VERSION 5.8 ;
BUSBITCHARS "[]" ;
DIVIDERCHAR "/" ;
UNITS
    DATABASE MICRONS 1000 ;
END UNITS

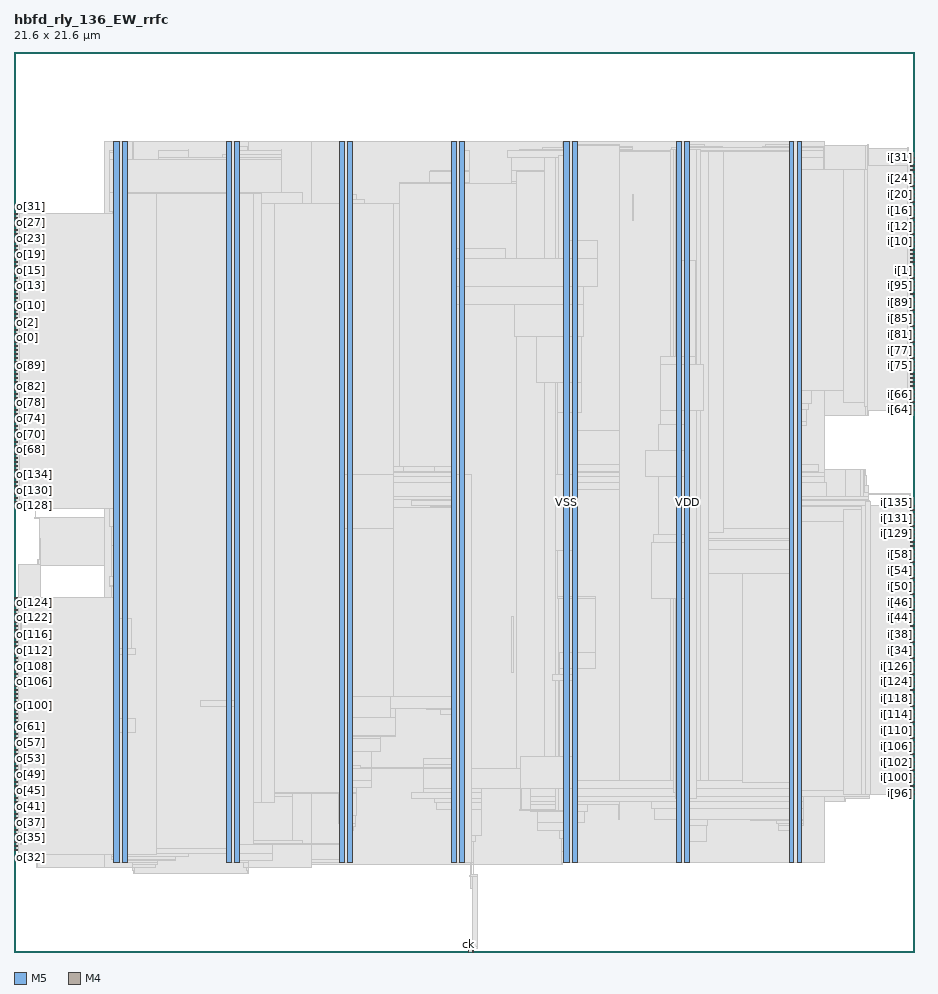
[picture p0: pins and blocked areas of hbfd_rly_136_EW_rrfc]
MACRO hbfd_rly_136_EW_rrfc
  FOREIGN hbfd_rly_136_EW_rrfc 0 0 ;
  CLASS BLOCK ;
  SIZE 21.6 BY 21.6 ;
  PIN ck
    DIRECTION INPUT ;
    USE SIGNAL ;
    PORT
      LAYER M5 ;
        RECT  10.896 0 10.92 0.084 ;
    END
  END ck
  PIN i[0]
    DIRECTION INPUT ;
    USE SIGNAL ;
    PORT
      LAYER M4 ;
        RECT  21.516 16.08 21.6 16.104 ;
    END
  END i[0]
  PIN i[100]
    DIRECTION INPUT ;
    USE SIGNAL ;
    PORT
      LAYER M4 ;
        RECT  21.516 4.176 21.6 4.2 ;
    END
  END i[100]
  PIN i[101]
    DIRECTION INPUT ;
    USE SIGNAL ;
    PORT
      LAYER M4 ;
        RECT  21.516 4.272 21.6 4.296 ;
    END
  END i[101]
  PIN i[102]
    DIRECTION INPUT ;
    USE SIGNAL ;
    PORT
      LAYER M4 ;
        RECT  21.516 4.368 21.6 4.392 ;
    END
  END i[102]
  PIN i[103]
    DIRECTION INPUT ;
    USE SIGNAL ;
    PORT
      LAYER M4 ;
        RECT  21.516 4.464 21.6 4.488 ;
    END
  END i[103]
  PIN i[104]
    DIRECTION INPUT ;
    USE SIGNAL ;
    PORT
      LAYER M4 ;
        RECT  21.516 4.56 21.6 4.584 ;
    END
  END i[104]
  PIN i[105]
    DIRECTION INPUT ;
    USE SIGNAL ;
    PORT
      LAYER M4 ;
        RECT  21.516 4.656 21.6 4.68 ;
    END
  END i[105]
  PIN i[106]
    DIRECTION INPUT ;
    USE SIGNAL ;
    PORT
      LAYER M4 ;
        RECT  21.516 4.752 21.6 4.776 ;
    END
  END i[106]
  PIN i[107]
    DIRECTION INPUT ;
    USE SIGNAL ;
    PORT
      LAYER M4 ;
        RECT  21.516 4.848 21.6 4.872 ;
    END
  END i[107]
  PIN i[108]
    DIRECTION INPUT ;
    USE SIGNAL ;
    PORT
      LAYER M4 ;
        RECT  21.516 4.944 21.6 4.968 ;
    END
  END i[108]
  PIN i[109]
    DIRECTION INPUT ;
    USE SIGNAL ;
    PORT
      LAYER M4 ;
        RECT  21.516 5.04 21.6 5.064 ;
    END
  END i[109]
  PIN i[10]
    DIRECTION INPUT ;
    USE SIGNAL ;
    PORT
      LAYER M4 ;
        RECT  21.516 17.04 21.6 17.064 ;
    END
  END i[10]
  PIN i[110]
    DIRECTION INPUT ;
    USE SIGNAL ;
    PORT
      LAYER M4 ;
        RECT  21.516 5.136 21.6 5.16 ;
    END
  END i[110]
  PIN i[111]
    DIRECTION INPUT ;
    USE SIGNAL ;
    PORT
      LAYER M4 ;
        RECT  21.516 5.232 21.6 5.256 ;
    END
  END i[111]
  PIN i[112]
    DIRECTION INPUT ;
    USE SIGNAL ;
    PORT
      LAYER M4 ;
        RECT  21.516 5.328 21.6 5.352 ;
    END
  END i[112]
  PIN i[113]
    DIRECTION INPUT ;
    USE SIGNAL ;
    PORT
      LAYER M4 ;
        RECT  21.516 5.424 21.6 5.448 ;
    END
  END i[113]
  PIN i[114]
    DIRECTION INPUT ;
    USE SIGNAL ;
    PORT
      LAYER M4 ;
        RECT  21.516 5.52 21.6 5.544 ;
    END
  END i[114]
  PIN i[115]
    DIRECTION INPUT ;
    USE SIGNAL ;
    PORT
      LAYER M4 ;
        RECT  21.516 5.616 21.6 5.64 ;
    END
  END i[115]
  PIN i[116]
    DIRECTION INPUT ;
    USE SIGNAL ;
    PORT
      LAYER M4 ;
        RECT  21.516 5.712 21.6 5.736 ;
    END
  END i[116]
  PIN i[117]
    DIRECTION INPUT ;
    USE SIGNAL ;
    PORT
      LAYER M4 ;
        RECT  21.516 5.808 21.6 5.832 ;
    END
  END i[117]
  PIN i[118]
    DIRECTION INPUT ;
    USE SIGNAL ;
    PORT
      LAYER M4 ;
        RECT  21.516 5.904 21.6 5.928 ;
    END
  END i[118]
  PIN i[119]
    DIRECTION INPUT ;
    USE SIGNAL ;
    PORT
      LAYER M4 ;
        RECT  21.516 6 21.6 6.024 ;
    END
  END i[119]
  PIN i[11]
    DIRECTION INPUT ;
    USE SIGNAL ;
    PORT
      LAYER M4 ;
        RECT  21.516 17.136 21.6 17.16 ;
    END
  END i[11]
  PIN i[120]
    DIRECTION INPUT ;
    USE SIGNAL ;
    PORT
      LAYER M4 ;
        RECT  21.516 6.096 21.6 6.12 ;
    END
  END i[120]
  PIN i[121]
    DIRECTION INPUT ;
    USE SIGNAL ;
    PORT
      LAYER M4 ;
        RECT  21.516 6.192 21.6 6.216 ;
    END
  END i[121]
  PIN i[122]
    DIRECTION INPUT ;
    USE SIGNAL ;
    PORT
      LAYER M4 ;
        RECT  21.516 6.288 21.6 6.312 ;
    END
  END i[122]
  PIN i[123]
    DIRECTION INPUT ;
    USE SIGNAL ;
    PORT
      LAYER M4 ;
        RECT  21.516 6.384 21.6 6.408 ;
    END
  END i[123]
  PIN i[124]
    DIRECTION INPUT ;
    USE SIGNAL ;
    PORT
      LAYER M4 ;
        RECT  21.516 6.48 21.6 6.504 ;
    END
  END i[124]
  PIN i[125]
    DIRECTION INPUT ;
    USE SIGNAL ;
    PORT
      LAYER M4 ;
        RECT  21.516 6.576 21.6 6.6 ;
    END
  END i[125]
  PIN i[126]
    DIRECTION INPUT ;
    USE SIGNAL ;
    PORT
      LAYER M4 ;
        RECT  21.516 6.672 21.6 6.696 ;
    END
  END i[126]
  PIN i[127]
    DIRECTION INPUT ;
    USE SIGNAL ;
    PORT
      LAYER M4 ;
        RECT  21.516 6.768 21.6 6.792 ;
    END
  END i[127]
  PIN i[128]
    DIRECTION INPUT ;
    USE SIGNAL ;
    PORT
      LAYER M4 ;
        RECT  21.516 9.936 21.6 9.96 ;
    END
  END i[128]
  PIN i[129]
    DIRECTION INPUT ;
    USE SIGNAL ;
    PORT
      LAYER M4 ;
        RECT  21.516 10.032 21.6 10.056 ;
    END
  END i[129]
  PIN i[12]
    DIRECTION INPUT ;
    USE SIGNAL ;
    PORT
      LAYER M4 ;
        RECT  21.516 17.232 21.6 17.256 ;
    END
  END i[12]
  PIN i[130]
    DIRECTION INPUT ;
    USE SIGNAL ;
    PORT
      LAYER M4 ;
        RECT  21.516 10.128 21.6 10.152 ;
    END
  END i[130]
  PIN i[131]
    DIRECTION INPUT ;
    USE SIGNAL ;
    PORT
      LAYER M4 ;
        RECT  21.516 10.224 21.6 10.248 ;
    END
  END i[131]
  PIN i[132]
    DIRECTION INPUT ;
    USE SIGNAL ;
    PORT
      LAYER M4 ;
        RECT  21.516 10.32 21.6 10.344 ;
    END
  END i[132]
  PIN i[133]
    DIRECTION INPUT ;
    USE SIGNAL ;
    PORT
      LAYER M4 ;
        RECT  21.516 10.416 21.6 10.44 ;
    END
  END i[133]
  PIN i[134]
    DIRECTION INPUT ;
    USE SIGNAL ;
    PORT
      LAYER M4 ;
        RECT  21.516 10.512 21.6 10.536 ;
    END
  END i[134]
  PIN i[135]
    DIRECTION INPUT ;
    USE SIGNAL ;
    PORT
      LAYER M4 ;
        RECT  21.516 10.608 21.6 10.632 ;
    END
  END i[135]
  PIN i[13]
    DIRECTION INPUT ;
    USE SIGNAL ;
    PORT
      LAYER M4 ;
        RECT  21.516 17.328 21.6 17.352 ;
    END
  END i[13]
  PIN i[14]
    DIRECTION INPUT ;
    USE SIGNAL ;
    PORT
      LAYER M4 ;
        RECT  21.516 17.424 21.6 17.448 ;
    END
  END i[14]
  PIN i[15]
    DIRECTION INPUT ;
    USE SIGNAL ;
    PORT
      LAYER M4 ;
        RECT  21.516 17.52 21.6 17.544 ;
    END
  END i[15]
  PIN i[16]
    DIRECTION INPUT ;
    USE SIGNAL ;
    PORT
      LAYER M4 ;
        RECT  21.516 17.616 21.6 17.64 ;
    END
  END i[16]
  PIN i[17]
    DIRECTION INPUT ;
    USE SIGNAL ;
    PORT
      LAYER M4 ;
        RECT  21.516 17.712 21.6 17.736 ;
    END
  END i[17]
  PIN i[18]
    DIRECTION INPUT ;
    USE SIGNAL ;
    PORT
      LAYER M4 ;
        RECT  21.516 17.808 21.6 17.832 ;
    END
  END i[18]
  PIN i[19]
    DIRECTION INPUT ;
    USE SIGNAL ;
    PORT
      LAYER M4 ;
        RECT  21.516 17.904 21.6 17.928 ;
    END
  END i[19]
  PIN i[1]
    DIRECTION INPUT ;
    USE SIGNAL ;
    PORT
      LAYER M4 ;
        RECT  21.516 16.176 21.6 16.2 ;
    END
  END i[1]
  PIN i[20]
    DIRECTION INPUT ;
    USE SIGNAL ;
    PORT
      LAYER M4 ;
        RECT  21.516 18 21.6 18.024 ;
    END
  END i[20]
  PIN i[21]
    DIRECTION INPUT ;
    USE SIGNAL ;
    PORT
      LAYER M4 ;
        RECT  21.516 18.096 21.6 18.12 ;
    END
  END i[21]
  PIN i[22]
    DIRECTION INPUT ;
    USE SIGNAL ;
    PORT
      LAYER M4 ;
        RECT  21.516 18.192 21.6 18.216 ;
    END
  END i[22]
  PIN i[23]
    DIRECTION INPUT ;
    USE SIGNAL ;
    PORT
      LAYER M4 ;
        RECT  21.516 18.288 21.6 18.312 ;
    END
  END i[23]
  PIN i[24]
    DIRECTION INPUT ;
    USE SIGNAL ;
    PORT
      LAYER M4 ;
        RECT  21.516 18.384 21.6 18.408 ;
    END
  END i[24]
  PIN i[25]
    DIRECTION INPUT ;
    USE SIGNAL ;
    PORT
      LAYER M4 ;
        RECT  21.516 18.48 21.6 18.504 ;
    END
  END i[25]
  PIN i[26]
    DIRECTION INPUT ;
    USE SIGNAL ;
    PORT
      LAYER M4 ;
        RECT  21.516 18.576 21.6 18.6 ;
    END
  END i[26]
  PIN i[27]
    DIRECTION INPUT ;
    USE SIGNAL ;
    PORT
      LAYER M4 ;
        RECT  21.516 18.672 21.6 18.696 ;
    END
  END i[27]
  PIN i[28]
    DIRECTION INPUT ;
    USE SIGNAL ;
    PORT
      LAYER M4 ;
        RECT  21.516 18.768 21.6 18.792 ;
    END
  END i[28]
  PIN i[29]
    DIRECTION INPUT ;
    USE SIGNAL ;
    PORT
      LAYER M4 ;
        RECT  21.516 18.864 21.6 18.888 ;
    END
  END i[29]
  PIN i[2]
    DIRECTION INPUT ;
    USE SIGNAL ;
    PORT
      LAYER M4 ;
        RECT  21.516 16.272 21.6 16.296 ;
    END
  END i[2]
  PIN i[30]
    DIRECTION INPUT ;
    USE SIGNAL ;
    PORT
      LAYER M4 ;
        RECT  21.516 18.96 21.6 18.984 ;
    END
  END i[30]
  PIN i[31]
    DIRECTION INPUT ;
    USE SIGNAL ;
    PORT
      LAYER M4 ;
        RECT  21.516 19.056 21.6 19.08 ;
    END
  END i[31]
  PIN i[32]
    DIRECTION INPUT ;
    USE SIGNAL ;
    PORT
      LAYER M4 ;
        RECT  21.516 6.864 21.6 6.888 ;
    END
  END i[32]
  PIN i[33]
    DIRECTION INPUT ;
    USE SIGNAL ;
    PORT
      LAYER M4 ;
        RECT  21.516 6.96 21.6 6.984 ;
    END
  END i[33]
  PIN i[34]
    DIRECTION INPUT ;
    USE SIGNAL ;
    PORT
      LAYER M4 ;
        RECT  21.516 7.056 21.6 7.08 ;
    END
  END i[34]
  PIN i[35]
    DIRECTION INPUT ;
    USE SIGNAL ;
    PORT
      LAYER M4 ;
        RECT  21.516 7.152 21.6 7.176 ;
    END
  END i[35]
  PIN i[36]
    DIRECTION INPUT ;
    USE SIGNAL ;
    PORT
      LAYER M4 ;
        RECT  21.516 7.248 21.6 7.272 ;
    END
  END i[36]
  PIN i[37]
    DIRECTION INPUT ;
    USE SIGNAL ;
    PORT
      LAYER M4 ;
        RECT  21.516 7.344 21.6 7.368 ;
    END
  END i[37]
  PIN i[38]
    DIRECTION INPUT ;
    USE SIGNAL ;
    PORT
      LAYER M4 ;
        RECT  21.516 7.44 21.6 7.464 ;
    END
  END i[38]
  PIN i[39]
    DIRECTION INPUT ;
    USE SIGNAL ;
    PORT
      LAYER M4 ;
        RECT  21.516 7.536 21.6 7.56 ;
    END
  END i[39]
  PIN i[3]
    DIRECTION INPUT ;
    USE SIGNAL ;
    PORT
      LAYER M4 ;
        RECT  21.516 16.368 21.6 16.392 ;
    END
  END i[3]
  PIN i[40]
    DIRECTION INPUT ;
    USE SIGNAL ;
    PORT
      LAYER M4 ;
        RECT  21.516 7.632 21.6 7.656 ;
    END
  END i[40]
  PIN i[41]
    DIRECTION INPUT ;
    USE SIGNAL ;
    PORT
      LAYER M4 ;
        RECT  21.516 7.728 21.6 7.752 ;
    END
  END i[41]
  PIN i[42]
    DIRECTION INPUT ;
    USE SIGNAL ;
    PORT
      LAYER M4 ;
        RECT  21.516 7.824 21.6 7.848 ;
    END
  END i[42]
  PIN i[43]
    DIRECTION INPUT ;
    USE SIGNAL ;
    PORT
      LAYER M4 ;
        RECT  21.516 7.92 21.6 7.944 ;
    END
  END i[43]
  PIN i[44]
    DIRECTION INPUT ;
    USE SIGNAL ;
    PORT
      LAYER M4 ;
        RECT  21.516 8.016 21.6 8.04 ;
    END
  END i[44]
  PIN i[45]
    DIRECTION INPUT ;
    USE SIGNAL ;
    PORT
      LAYER M4 ;
        RECT  21.516 8.112 21.6 8.136 ;
    END
  END i[45]
  PIN i[46]
    DIRECTION INPUT ;
    USE SIGNAL ;
    PORT
      LAYER M4 ;
        RECT  21.516 8.208 21.6 8.232 ;
    END
  END i[46]
  PIN i[47]
    DIRECTION INPUT ;
    USE SIGNAL ;
    PORT
      LAYER M4 ;
        RECT  21.516 8.304 21.6 8.328 ;
    END
  END i[47]
  PIN i[48]
    DIRECTION INPUT ;
    USE SIGNAL ;
    PORT
      LAYER M4 ;
        RECT  21.516 8.4 21.6 8.424 ;
    END
  END i[48]
  PIN i[49]
    DIRECTION INPUT ;
    USE SIGNAL ;
    PORT
      LAYER M4 ;
        RECT  21.516 8.496 21.6 8.52 ;
    END
  END i[49]
  PIN i[4]
    DIRECTION INPUT ;
    USE SIGNAL ;
    PORT
      LAYER M4 ;
        RECT  21.516 16.464 21.6 16.488 ;
    END
  END i[4]
  PIN i[50]
    DIRECTION INPUT ;
    USE SIGNAL ;
    PORT
      LAYER M4 ;
        RECT  21.516 8.592 21.6 8.616 ;
    END
  END i[50]
  PIN i[51]
    DIRECTION INPUT ;
    USE SIGNAL ;
    PORT
      LAYER M4 ;
        RECT  21.516 8.688 21.6 8.712 ;
    END
  END i[51]
  PIN i[52]
    DIRECTION INPUT ;
    USE SIGNAL ;
    PORT
      LAYER M4 ;
        RECT  21.516 8.784 21.6 8.808 ;
    END
  END i[52]
  PIN i[53]
    DIRECTION INPUT ;
    USE SIGNAL ;
    PORT
      LAYER M4 ;
        RECT  21.516 8.88 21.6 8.904 ;
    END
  END i[53]
  PIN i[54]
    DIRECTION INPUT ;
    USE SIGNAL ;
    PORT
      LAYER M4 ;
        RECT  21.516 8.976 21.6 9 ;
    END
  END i[54]
  PIN i[55]
    DIRECTION INPUT ;
    USE SIGNAL ;
    PORT
      LAYER M4 ;
        RECT  21.516 9.072 21.6 9.096 ;
    END
  END i[55]
  PIN i[56]
    DIRECTION INPUT ;
    USE SIGNAL ;
    PORT
      LAYER M4 ;
        RECT  21.516 9.168 21.6 9.192 ;
    END
  END i[56]
  PIN i[57]
    DIRECTION INPUT ;
    USE SIGNAL ;
    PORT
      LAYER M4 ;
        RECT  21.516 9.264 21.6 9.288 ;
    END
  END i[57]
  PIN i[58]
    DIRECTION INPUT ;
    USE SIGNAL ;
    PORT
      LAYER M4 ;
        RECT  21.516 9.36 21.6 9.384 ;
    END
  END i[58]
  PIN i[59]
    DIRECTION INPUT ;
    USE SIGNAL ;
    PORT
      LAYER M4 ;
        RECT  21.516 9.456 21.6 9.48 ;
    END
  END i[59]
  PIN i[5]
    DIRECTION INPUT ;
    USE SIGNAL ;
    PORT
      LAYER M4 ;
        RECT  21.516 16.56 21.6 16.584 ;
    END
  END i[5]
  PIN i[60]
    DIRECTION INPUT ;
    USE SIGNAL ;
    PORT
      LAYER M4 ;
        RECT  21.516 9.552 21.6 9.576 ;
    END
  END i[60]
  PIN i[61]
    DIRECTION INPUT ;
    USE SIGNAL ;
    PORT
      LAYER M4 ;
        RECT  21.516 9.648 21.6 9.672 ;
    END
  END i[61]
  PIN i[62]
    DIRECTION INPUT ;
    USE SIGNAL ;
    PORT
      LAYER M4 ;
        RECT  21.516 9.744 21.6 9.768 ;
    END
  END i[62]
  PIN i[63]
    DIRECTION INPUT ;
    USE SIGNAL ;
    PORT
      LAYER M4 ;
        RECT  21.516 9.84 21.6 9.864 ;
    END
  END i[63]
  PIN i[64]
    DIRECTION INPUT ;
    USE SIGNAL ;
    PORT
      LAYER M4 ;
        RECT  21.516 13.008 21.6 13.032 ;
    END
  END i[64]
  PIN i[65]
    DIRECTION INPUT ;
    USE SIGNAL ;
    PORT
      LAYER M4 ;
        RECT  21.516 13.104 21.6 13.128 ;
    END
  END i[65]
  PIN i[66]
    DIRECTION INPUT ;
    USE SIGNAL ;
    PORT
      LAYER M4 ;
        RECT  21.516 13.2 21.6 13.224 ;
    END
  END i[66]
  PIN i[67]
    DIRECTION INPUT ;
    USE SIGNAL ;
    PORT
      LAYER M4 ;
        RECT  21.516 13.296 21.6 13.32 ;
    END
  END i[67]
  PIN i[68]
    DIRECTION INPUT ;
    USE SIGNAL ;
    PORT
      LAYER M4 ;
        RECT  21.516 13.392 21.6 13.416 ;
    END
  END i[68]
  PIN i[69]
    DIRECTION INPUT ;
    USE SIGNAL ;
    PORT
      LAYER M4 ;
        RECT  21.516 13.488 21.6 13.512 ;
    END
  END i[69]
  PIN i[6]
    DIRECTION INPUT ;
    USE SIGNAL ;
    PORT
      LAYER M4 ;
        RECT  21.516 16.656 21.6 16.68 ;
    END
  END i[6]
  PIN i[70]
    DIRECTION INPUT ;
    USE SIGNAL ;
    PORT
      LAYER M4 ;
        RECT  21.516 13.584 21.6 13.608 ;
    END
  END i[70]
  PIN i[71]
    DIRECTION INPUT ;
    USE SIGNAL ;
    PORT
      LAYER M4 ;
        RECT  21.516 13.68 21.6 13.704 ;
    END
  END i[71]
  PIN i[72]
    DIRECTION INPUT ;
    USE SIGNAL ;
    PORT
      LAYER M4 ;
        RECT  21.516 13.776 21.6 13.8 ;
    END
  END i[72]
  PIN i[73]
    DIRECTION INPUT ;
    USE SIGNAL ;
    PORT
      LAYER M4 ;
        RECT  21.516 13.872 21.6 13.896 ;
    END
  END i[73]
  PIN i[74]
    DIRECTION INPUT ;
    USE SIGNAL ;
    PORT
      LAYER M4 ;
        RECT  21.516 13.968 21.6 13.992 ;
    END
  END i[74]
  PIN i[75]
    DIRECTION INPUT ;
    USE SIGNAL ;
    PORT
      LAYER M4 ;
        RECT  21.516 14.064 21.6 14.088 ;
    END
  END i[75]
  PIN i[76]
    DIRECTION INPUT ;
    USE SIGNAL ;
    PORT
      LAYER M4 ;
        RECT  21.516 14.16 21.6 14.184 ;
    END
  END i[76]
  PIN i[77]
    DIRECTION INPUT ;
    USE SIGNAL ;
    PORT
      LAYER M4 ;
        RECT  21.516 14.256 21.6 14.28 ;
    END
  END i[77]
  PIN i[78]
    DIRECTION INPUT ;
    USE SIGNAL ;
    PORT
      LAYER M4 ;
        RECT  21.516 14.352 21.6 14.376 ;
    END
  END i[78]
  PIN i[79]
    DIRECTION INPUT ;
    USE SIGNAL ;
    PORT
      LAYER M4 ;
        RECT  21.516 14.448 21.6 14.472 ;
    END
  END i[79]
  PIN i[7]
    DIRECTION INPUT ;
    USE SIGNAL ;
    PORT
      LAYER M4 ;
        RECT  21.516 16.752 21.6 16.776 ;
    END
  END i[7]
  PIN i[80]
    DIRECTION INPUT ;
    USE SIGNAL ;
    PORT
      LAYER M4 ;
        RECT  21.516 14.544 21.6 14.568 ;
    END
  END i[80]
  PIN i[81]
    DIRECTION INPUT ;
    USE SIGNAL ;
    PORT
      LAYER M4 ;
        RECT  21.516 14.64 21.6 14.664 ;
    END
  END i[81]
  PIN i[82]
    DIRECTION INPUT ;
    USE SIGNAL ;
    PORT
      LAYER M4 ;
        RECT  21.516 14.736 21.6 14.76 ;
    END
  END i[82]
  PIN i[83]
    DIRECTION INPUT ;
    USE SIGNAL ;
    PORT
      LAYER M4 ;
        RECT  21.516 14.832 21.6 14.856 ;
    END
  END i[83]
  PIN i[84]
    DIRECTION INPUT ;
    USE SIGNAL ;
    PORT
      LAYER M4 ;
        RECT  21.516 14.928 21.6 14.952 ;
    END
  END i[84]
  PIN i[85]
    DIRECTION INPUT ;
    USE SIGNAL ;
    PORT
      LAYER M4 ;
        RECT  21.516 15.024 21.6 15.048 ;
    END
  END i[85]
  PIN i[86]
    DIRECTION INPUT ;
    USE SIGNAL ;
    PORT
      LAYER M4 ;
        RECT  21.516 15.12 21.6 15.144 ;
    END
  END i[86]
  PIN i[87]
    DIRECTION INPUT ;
    USE SIGNAL ;
    PORT
      LAYER M4 ;
        RECT  21.516 15.216 21.6 15.24 ;
    END
  END i[87]
  PIN i[88]
    DIRECTION INPUT ;
    USE SIGNAL ;
    PORT
      LAYER M4 ;
        RECT  21.516 15.312 21.6 15.336 ;
    END
  END i[88]
  PIN i[89]
    DIRECTION INPUT ;
    USE SIGNAL ;
    PORT
      LAYER M4 ;
        RECT  21.516 15.408 21.6 15.432 ;
    END
  END i[89]
  PIN i[8]
    DIRECTION INPUT ;
    USE SIGNAL ;
    PORT
      LAYER M4 ;
        RECT  21.516 16.848 21.6 16.872 ;
    END
  END i[8]
  PIN i[90]
    DIRECTION INPUT ;
    USE SIGNAL ;
    PORT
      LAYER M4 ;
        RECT  21.516 15.504 21.6 15.528 ;
    END
  END i[90]
  PIN i[91]
    DIRECTION INPUT ;
    USE SIGNAL ;
    PORT
      LAYER M4 ;
        RECT  21.516 15.6 21.6 15.624 ;
    END
  END i[91]
  PIN i[92]
    DIRECTION INPUT ;
    USE SIGNAL ;
    PORT
      LAYER M4 ;
        RECT  21.516 15.696 21.6 15.72 ;
    END
  END i[92]
  PIN i[93]
    DIRECTION INPUT ;
    USE SIGNAL ;
    PORT
      LAYER M4 ;
        RECT  21.516 15.792 21.6 15.816 ;
    END
  END i[93]
  PIN i[94]
    DIRECTION INPUT ;
    USE SIGNAL ;
    PORT
      LAYER M4 ;
        RECT  21.516 15.888 21.6 15.912 ;
    END
  END i[94]
  PIN i[95]
    DIRECTION INPUT ;
    USE SIGNAL ;
    PORT
      LAYER M4 ;
        RECT  21.516 15.984 21.6 16.008 ;
    END
  END i[95]
  PIN i[96]
    DIRECTION INPUT ;
    USE SIGNAL ;
    PORT
      LAYER M4 ;
        RECT  21.516 3.792 21.6 3.816 ;
    END
  END i[96]
  PIN i[97]
    DIRECTION INPUT ;
    USE SIGNAL ;
    PORT
      LAYER M4 ;
        RECT  21.516 3.888 21.6 3.912 ;
    END
  END i[97]
  PIN i[98]
    DIRECTION INPUT ;
    USE SIGNAL ;
    PORT
      LAYER M4 ;
        RECT  21.516 3.984 21.6 4.008 ;
    END
  END i[98]
  PIN i[99]
    DIRECTION INPUT ;
    USE SIGNAL ;
    PORT
      LAYER M4 ;
        RECT  21.516 4.08 21.6 4.104 ;
    END
  END i[99]
  PIN i[9]
    DIRECTION INPUT ;
    USE SIGNAL ;
    PORT
      LAYER M4 ;
        RECT  21.516 16.944 21.6 16.968 ;
    END
  END i[9]
  PIN o[0]
    DIRECTION OUTPUT ;
    USE SIGNAL ;
    PORT
      LAYER M4 ;
        RECT  0 14.736 0.084 14.76 ;
    END
  END o[0]
  PIN o[100]
    DIRECTION OUTPUT ;
    USE SIGNAL ;
    PORT
      LAYER M4 ;
        RECT  0 5.904 0.084 5.928 ;
    END
  END o[100]
  PIN o[101]
    DIRECTION OUTPUT ;
    USE SIGNAL ;
    PORT
      LAYER M4 ;
        RECT  0 6 0.084 6.024 ;
    END
  END o[101]
  PIN o[102]
    DIRECTION OUTPUT ;
    USE SIGNAL ;
    PORT
      LAYER M4 ;
        RECT  0 6.096 0.084 6.12 ;
    END
  END o[102]
  PIN o[103]
    DIRECTION OUTPUT ;
    USE SIGNAL ;
    PORT
      LAYER M4 ;
        RECT  0 6.192 0.084 6.216 ;
    END
  END o[103]
  PIN o[104]
    DIRECTION OUTPUT ;
    USE SIGNAL ;
    PORT
      LAYER M4 ;
        RECT  0 6.288 0.084 6.312 ;
    END
  END o[104]
  PIN o[105]
    DIRECTION OUTPUT ;
    USE SIGNAL ;
    PORT
      LAYER M4 ;
        RECT  0 6.384 0.084 6.408 ;
    END
  END o[105]
  PIN o[106]
    DIRECTION OUTPUT ;
    USE SIGNAL ;
    PORT
      LAYER M4 ;
        RECT  0 6.48 0.084 6.504 ;
    END
  END o[106]
  PIN o[107]
    DIRECTION OUTPUT ;
    USE SIGNAL ;
    PORT
      LAYER M4 ;
        RECT  0 6.576 0.084 6.6 ;
    END
  END o[107]
  PIN o[108]
    DIRECTION OUTPUT ;
    USE SIGNAL ;
    PORT
      LAYER M4 ;
        RECT  0 6.672 0.084 6.696 ;
    END
  END o[108]
  PIN o[109]
    DIRECTION OUTPUT ;
    USE SIGNAL ;
    PORT
      LAYER M4 ;
        RECT  0 6.768 0.084 6.792 ;
    END
  END o[109]
  PIN o[10]
    DIRECTION OUTPUT ;
    USE SIGNAL ;
    PORT
      LAYER M4 ;
        RECT  0 15.696 0.084 15.72 ;
    END
  END o[10]
  PIN o[110]
    DIRECTION OUTPUT ;
    USE SIGNAL ;
    PORT
      LAYER M4 ;
        RECT  0 6.864 0.084 6.888 ;
    END
  END o[110]
  PIN o[111]
    DIRECTION OUTPUT ;
    USE SIGNAL ;
    PORT
      LAYER M4 ;
        RECT  0 6.96 0.084 6.984 ;
    END
  END o[111]
  PIN o[112]
    DIRECTION OUTPUT ;
    USE SIGNAL ;
    PORT
      LAYER M4 ;
        RECT  0 7.056 0.084 7.08 ;
    END
  END o[112]
  PIN o[113]
    DIRECTION OUTPUT ;
    USE SIGNAL ;
    PORT
      LAYER M4 ;
        RECT  0 7.152 0.084 7.176 ;
    END
  END o[113]
  PIN o[114]
    DIRECTION OUTPUT ;
    USE SIGNAL ;
    PORT
      LAYER M4 ;
        RECT  0 7.248 0.084 7.272 ;
    END
  END o[114]
  PIN o[115]
    DIRECTION OUTPUT ;
    USE SIGNAL ;
    PORT
      LAYER M4 ;
        RECT  0 7.344 0.084 7.368 ;
    END
  END o[115]
  PIN o[116]
    DIRECTION OUTPUT ;
    USE SIGNAL ;
    PORT
      LAYER M4 ;
        RECT  0 7.44 0.084 7.464 ;
    END
  END o[116]
  PIN o[117]
    DIRECTION OUTPUT ;
    USE SIGNAL ;
    PORT
      LAYER M4 ;
        RECT  0 7.536 0.084 7.56 ;
    END
  END o[117]
  PIN o[118]
    DIRECTION OUTPUT ;
    USE SIGNAL ;
    PORT
      LAYER M4 ;
        RECT  0 7.632 0.084 7.656 ;
    END
  END o[118]
  PIN o[119]
    DIRECTION OUTPUT ;
    USE SIGNAL ;
    PORT
      LAYER M4 ;
        RECT  0 7.728 0.084 7.752 ;
    END
  END o[119]
  PIN o[11]
    DIRECTION OUTPUT ;
    USE SIGNAL ;
    PORT
      LAYER M4 ;
        RECT  0 15.792 0.084 15.816 ;
    END
  END o[11]
  PIN o[120]
    DIRECTION OUTPUT ;
    USE SIGNAL ;
    PORT
      LAYER M4 ;
        RECT  0 7.824 0.084 7.848 ;
    END
  END o[120]
  PIN o[121]
    DIRECTION OUTPUT ;
    USE SIGNAL ;
    PORT
      LAYER M4 ;
        RECT  0 7.92 0.084 7.944 ;
    END
  END o[121]
  PIN o[122]
    DIRECTION OUTPUT ;
    USE SIGNAL ;
    PORT
      LAYER M4 ;
        RECT  0 8.016 0.084 8.04 ;
    END
  END o[122]
  PIN o[123]
    DIRECTION OUTPUT ;
    USE SIGNAL ;
    PORT
      LAYER M4 ;
        RECT  0 8.112 0.084 8.136 ;
    END
  END o[123]
  PIN o[124]
    DIRECTION OUTPUT ;
    USE SIGNAL ;
    PORT
      LAYER M4 ;
        RECT  0 8.208 0.084 8.232 ;
    END
  END o[124]
  PIN o[125]
    DIRECTION OUTPUT ;
    USE SIGNAL ;
    PORT
      LAYER M4 ;
        RECT  0 8.304 0.084 8.328 ;
    END
  END o[125]
  PIN o[126]
    DIRECTION OUTPUT ;
    USE SIGNAL ;
    PORT
      LAYER M4 ;
        RECT  0 8.4 0.084 8.424 ;
    END
  END o[126]
  PIN o[127]
    DIRECTION OUTPUT ;
    USE SIGNAL ;
    PORT
      LAYER M4 ;
        RECT  0 8.496 0.084 8.52 ;
    END
  END o[127]
  PIN o[128]
    DIRECTION OUTPUT ;
    USE SIGNAL ;
    PORT
      LAYER M4 ;
        RECT  0 10.704 0.084 10.728 ;
    END
  END o[128]
  PIN o[129]
    DIRECTION OUTPUT ;
    USE SIGNAL ;
    PORT
      LAYER M4 ;
        RECT  0 10.8 0.084 10.824 ;
    END
  END o[129]
  PIN o[12]
    DIRECTION OUTPUT ;
    USE SIGNAL ;
    PORT
      LAYER M4 ;
        RECT  0 15.888 0.084 15.912 ;
    END
  END o[12]
  PIN o[130]
    DIRECTION OUTPUT ;
    USE SIGNAL ;
    PORT
      LAYER M4 ;
        RECT  0 10.896 0.084 10.92 ;
    END
  END o[130]
  PIN o[131]
    DIRECTION OUTPUT ;
    USE SIGNAL ;
    PORT
      LAYER M4 ;
        RECT  0 10.992 0.084 11.016 ;
    END
  END o[131]
  PIN o[132]
    DIRECTION OUTPUT ;
    USE SIGNAL ;
    PORT
      LAYER M4 ;
        RECT  0 11.088 0.084 11.112 ;
    END
  END o[132]
  PIN o[133]
    DIRECTION OUTPUT ;
    USE SIGNAL ;
    PORT
      LAYER M4 ;
        RECT  0 11.184 0.084 11.208 ;
    END
  END o[133]
  PIN o[134]
    DIRECTION OUTPUT ;
    USE SIGNAL ;
    PORT
      LAYER M4 ;
        RECT  0 11.28 0.084 11.304 ;
    END
  END o[134]
  PIN o[135]
    DIRECTION OUTPUT ;
    USE SIGNAL ;
    PORT
      LAYER M4 ;
        RECT  0 11.376 0.084 11.4 ;
    END
  END o[135]
  PIN o[13]
    DIRECTION OUTPUT ;
    USE SIGNAL ;
    PORT
      LAYER M4 ;
        RECT  0 15.984 0.084 16.008 ;
    END
  END o[13]
  PIN o[14]
    DIRECTION OUTPUT ;
    USE SIGNAL ;
    PORT
      LAYER M4 ;
        RECT  0 16.08 0.084 16.104 ;
    END
  END o[14]
  PIN o[15]
    DIRECTION OUTPUT ;
    USE SIGNAL ;
    PORT
      LAYER M4 ;
        RECT  0 16.176 0.084 16.2 ;
    END
  END o[15]
  PIN o[16]
    DIRECTION OUTPUT ;
    USE SIGNAL ;
    PORT
      LAYER M4 ;
        RECT  0 16.272 0.084 16.296 ;
    END
  END o[16]
  PIN o[17]
    DIRECTION OUTPUT ;
    USE SIGNAL ;
    PORT
      LAYER M4 ;
        RECT  0 16.368 0.084 16.392 ;
    END
  END o[17]
  PIN o[18]
    DIRECTION OUTPUT ;
    USE SIGNAL ;
    PORT
      LAYER M4 ;
        RECT  0 16.464 0.084 16.488 ;
    END
  END o[18]
  PIN o[19]
    DIRECTION OUTPUT ;
    USE SIGNAL ;
    PORT
      LAYER M4 ;
        RECT  0 16.56 0.084 16.584 ;
    END
  END o[19]
  PIN o[1]
    DIRECTION OUTPUT ;
    USE SIGNAL ;
    PORT
      LAYER M4 ;
        RECT  0 14.832 0.084 14.856 ;
    END
  END o[1]
  PIN o[20]
    DIRECTION OUTPUT ;
    USE SIGNAL ;
    PORT
      LAYER M4 ;
        RECT  0 16.656 0.084 16.68 ;
    END
  END o[20]
  PIN o[21]
    DIRECTION OUTPUT ;
    USE SIGNAL ;
    PORT
      LAYER M4 ;
        RECT  0 16.752 0.084 16.776 ;
    END
  END o[21]
  PIN o[22]
    DIRECTION OUTPUT ;
    USE SIGNAL ;
    PORT
      LAYER M4 ;
        RECT  0 16.848 0.084 16.872 ;
    END
  END o[22]
  PIN o[23]
    DIRECTION OUTPUT ;
    USE SIGNAL ;
    PORT
      LAYER M4 ;
        RECT  0 16.944 0.084 16.968 ;
    END
  END o[23]
  PIN o[24]
    DIRECTION OUTPUT ;
    USE SIGNAL ;
    PORT
      LAYER M4 ;
        RECT  0 17.04 0.084 17.064 ;
    END
  END o[24]
  PIN o[25]
    DIRECTION OUTPUT ;
    USE SIGNAL ;
    PORT
      LAYER M4 ;
        RECT  0 17.136 0.084 17.16 ;
    END
  END o[25]
  PIN o[26]
    DIRECTION OUTPUT ;
    USE SIGNAL ;
    PORT
      LAYER M4 ;
        RECT  0 17.232 0.084 17.256 ;
    END
  END o[26]
  PIN o[27]
    DIRECTION OUTPUT ;
    USE SIGNAL ;
    PORT
      LAYER M4 ;
        RECT  0 17.328 0.084 17.352 ;
    END
  END o[27]
  PIN o[28]
    DIRECTION OUTPUT ;
    USE SIGNAL ;
    PORT
      LAYER M4 ;
        RECT  0 17.424 0.084 17.448 ;
    END
  END o[28]
  PIN o[29]
    DIRECTION OUTPUT ;
    USE SIGNAL ;
    PORT
      LAYER M4 ;
        RECT  0 17.52 0.084 17.544 ;
    END
  END o[29]
  PIN o[2]
    DIRECTION OUTPUT ;
    USE SIGNAL ;
    PORT
      LAYER M4 ;
        RECT  0 14.928 0.084 14.952 ;
    END
  END o[2]
  PIN o[30]
    DIRECTION OUTPUT ;
    USE SIGNAL ;
    PORT
      LAYER M4 ;
        RECT  0 17.616 0.084 17.64 ;
    END
  END o[30]
  PIN o[31]
    DIRECTION OUTPUT ;
    USE SIGNAL ;
    PORT
      LAYER M4 ;
        RECT  0 17.712 0.084 17.736 ;
    END
  END o[31]
  PIN o[32]
    DIRECTION OUTPUT ;
    USE SIGNAL ;
    PORT
      LAYER M4 ;
        RECT  0 2.448 0.084 2.472 ;
    END
  END o[32]
  PIN o[33]
    DIRECTION OUTPUT ;
    USE SIGNAL ;
    PORT
      LAYER M4 ;
        RECT  0 2.544 0.084 2.568 ;
    END
  END o[33]
  PIN o[34]
    DIRECTION OUTPUT ;
    USE SIGNAL ;
    PORT
      LAYER M4 ;
        RECT  0 2.64 0.084 2.664 ;
    END
  END o[34]
  PIN o[35]
    DIRECTION OUTPUT ;
    USE SIGNAL ;
    PORT
      LAYER M4 ;
        RECT  0 2.736 0.084 2.76 ;
    END
  END o[35]
  PIN o[36]
    DIRECTION OUTPUT ;
    USE SIGNAL ;
    PORT
      LAYER M4 ;
        RECT  0 2.832 0.084 2.856 ;
    END
  END o[36]
  PIN o[37]
    DIRECTION OUTPUT ;
    USE SIGNAL ;
    PORT
      LAYER M4 ;
        RECT  0 2.928 0.084 2.952 ;
    END
  END o[37]
  PIN o[38]
    DIRECTION OUTPUT ;
    USE SIGNAL ;
    PORT
      LAYER M4 ;
        RECT  0 3.024 0.084 3.048 ;
    END
  END o[38]
  PIN o[39]
    DIRECTION OUTPUT ;
    USE SIGNAL ;
    PORT
      LAYER M4 ;
        RECT  0 3.12 0.084 3.144 ;
    END
  END o[39]
  PIN o[3]
    DIRECTION OUTPUT ;
    USE SIGNAL ;
    PORT
      LAYER M4 ;
        RECT  0 15.024 0.084 15.048 ;
    END
  END o[3]
  PIN o[40]
    DIRECTION OUTPUT ;
    USE SIGNAL ;
    PORT
      LAYER M4 ;
        RECT  0 3.216 0.084 3.24 ;
    END
  END o[40]
  PIN o[41]
    DIRECTION OUTPUT ;
    USE SIGNAL ;
    PORT
      LAYER M4 ;
        RECT  0 3.312 0.084 3.336 ;
    END
  END o[41]
  PIN o[42]
    DIRECTION OUTPUT ;
    USE SIGNAL ;
    PORT
      LAYER M4 ;
        RECT  0 3.408 0.084 3.432 ;
    END
  END o[42]
  PIN o[43]
    DIRECTION OUTPUT ;
    USE SIGNAL ;
    PORT
      LAYER M4 ;
        RECT  0 3.504 0.084 3.528 ;
    END
  END o[43]
  PIN o[44]
    DIRECTION OUTPUT ;
    USE SIGNAL ;
    PORT
      LAYER M4 ;
        RECT  0 3.6 0.084 3.624 ;
    END
  END o[44]
  PIN o[45]
    DIRECTION OUTPUT ;
    USE SIGNAL ;
    PORT
      LAYER M4 ;
        RECT  0 3.696 0.084 3.72 ;
    END
  END o[45]
  PIN o[46]
    DIRECTION OUTPUT ;
    USE SIGNAL ;
    PORT
      LAYER M4 ;
        RECT  0 3.792 0.084 3.816 ;
    END
  END o[46]
  PIN o[47]
    DIRECTION OUTPUT ;
    USE SIGNAL ;
    PORT
      LAYER M4 ;
        RECT  0 3.888 0.084 3.912 ;
    END
  END o[47]
  PIN o[48]
    DIRECTION OUTPUT ;
    USE SIGNAL ;
    PORT
      LAYER M4 ;
        RECT  0 3.984 0.084 4.008 ;
    END
  END o[48]
  PIN o[49]
    DIRECTION OUTPUT ;
    USE SIGNAL ;
    PORT
      LAYER M4 ;
        RECT  0 4.08 0.084 4.104 ;
    END
  END o[49]
  PIN o[4]
    DIRECTION OUTPUT ;
    USE SIGNAL ;
    PORT
      LAYER M4 ;
        RECT  0 15.12 0.084 15.144 ;
    END
  END o[4]
  PIN o[50]
    DIRECTION OUTPUT ;
    USE SIGNAL ;
    PORT
      LAYER M4 ;
        RECT  0 4.176 0.084 4.2 ;
    END
  END o[50]
  PIN o[51]
    DIRECTION OUTPUT ;
    USE SIGNAL ;
    PORT
      LAYER M4 ;
        RECT  0 4.272 0.084 4.296 ;
    END
  END o[51]
  PIN o[52]
    DIRECTION OUTPUT ;
    USE SIGNAL ;
    PORT
      LAYER M4 ;
        RECT  0 4.368 0.084 4.392 ;
    END
  END o[52]
  PIN o[53]
    DIRECTION OUTPUT ;
    USE SIGNAL ;
    PORT
      LAYER M4 ;
        RECT  0 4.464 0.084 4.488 ;
    END
  END o[53]
  PIN o[54]
    DIRECTION OUTPUT ;
    USE SIGNAL ;
    PORT
      LAYER M4 ;
        RECT  0 4.56 0.084 4.584 ;
    END
  END o[54]
  PIN o[55]
    DIRECTION OUTPUT ;
    USE SIGNAL ;
    PORT
      LAYER M4 ;
        RECT  0 4.656 0.084 4.68 ;
    END
  END o[55]
  PIN o[56]
    DIRECTION OUTPUT ;
    USE SIGNAL ;
    PORT
      LAYER M4 ;
        RECT  0 4.752 0.084 4.776 ;
    END
  END o[56]
  PIN o[57]
    DIRECTION OUTPUT ;
    USE SIGNAL ;
    PORT
      LAYER M4 ;
        RECT  0 4.848 0.084 4.872 ;
    END
  END o[57]
  PIN o[58]
    DIRECTION OUTPUT ;
    USE SIGNAL ;
    PORT
      LAYER M4 ;
        RECT  0 4.944 0.084 4.968 ;
    END
  END o[58]
  PIN o[59]
    DIRECTION OUTPUT ;
    USE SIGNAL ;
    PORT
      LAYER M4 ;
        RECT  0 5.04 0.084 5.064 ;
    END
  END o[59]
  PIN o[5]
    DIRECTION OUTPUT ;
    USE SIGNAL ;
    PORT
      LAYER M4 ;
        RECT  0 15.216 0.084 15.24 ;
    END
  END o[5]
  PIN o[60]
    DIRECTION OUTPUT ;
    USE SIGNAL ;
    PORT
      LAYER M4 ;
        RECT  0 5.136 0.084 5.16 ;
    END
  END o[60]
  PIN o[61]
    DIRECTION OUTPUT ;
    USE SIGNAL ;
    PORT
      LAYER M4 ;
        RECT  0 5.232 0.084 5.256 ;
    END
  END o[61]
  PIN o[62]
    DIRECTION OUTPUT ;
    USE SIGNAL ;
    PORT
      LAYER M4 ;
        RECT  0 5.328 0.084 5.352 ;
    END
  END o[62]
  PIN o[63]
    DIRECTION OUTPUT ;
    USE SIGNAL ;
    PORT
      LAYER M4 ;
        RECT  0 5.424 0.084 5.448 ;
    END
  END o[63]
  PIN o[64]
    DIRECTION OUTPUT ;
    USE SIGNAL ;
    PORT
      LAYER M4 ;
        RECT  0 11.664 0.084 11.688 ;
    END
  END o[64]
  PIN o[65]
    DIRECTION OUTPUT ;
    USE SIGNAL ;
    PORT
      LAYER M4 ;
        RECT  0 11.76 0.084 11.784 ;
    END
  END o[65]
  PIN o[66]
    DIRECTION OUTPUT ;
    USE SIGNAL ;
    PORT
      LAYER M4 ;
        RECT  0 11.856 0.084 11.88 ;
    END
  END o[66]
  PIN o[67]
    DIRECTION OUTPUT ;
    USE SIGNAL ;
    PORT
      LAYER M4 ;
        RECT  0 11.952 0.084 11.976 ;
    END
  END o[67]
  PIN o[68]
    DIRECTION OUTPUT ;
    USE SIGNAL ;
    PORT
      LAYER M4 ;
        RECT  0 12.048 0.084 12.072 ;
    END
  END o[68]
  PIN o[69]
    DIRECTION OUTPUT ;
    USE SIGNAL ;
    PORT
      LAYER M4 ;
        RECT  0 12.144 0.084 12.168 ;
    END
  END o[69]
  PIN o[6]
    DIRECTION OUTPUT ;
    USE SIGNAL ;
    PORT
      LAYER M4 ;
        RECT  0 15.312 0.084 15.336 ;
    END
  END o[6]
  PIN o[70]
    DIRECTION OUTPUT ;
    USE SIGNAL ;
    PORT
      LAYER M4 ;
        RECT  0 12.24 0.084 12.264 ;
    END
  END o[70]
  PIN o[71]
    DIRECTION OUTPUT ;
    USE SIGNAL ;
    PORT
      LAYER M4 ;
        RECT  0 12.336 0.084 12.36 ;
    END
  END o[71]
  PIN o[72]
    DIRECTION OUTPUT ;
    USE SIGNAL ;
    PORT
      LAYER M4 ;
        RECT  0 12.432 0.084 12.456 ;
    END
  END o[72]
  PIN o[73]
    DIRECTION OUTPUT ;
    USE SIGNAL ;
    PORT
      LAYER M4 ;
        RECT  0 12.528 0.084 12.552 ;
    END
  END o[73]
  PIN o[74]
    DIRECTION OUTPUT ;
    USE SIGNAL ;
    PORT
      LAYER M4 ;
        RECT  0 12.624 0.084 12.648 ;
    END
  END o[74]
  PIN o[75]
    DIRECTION OUTPUT ;
    USE SIGNAL ;
    PORT
      LAYER M4 ;
        RECT  0 12.72 0.084 12.744 ;
    END
  END o[75]
  PIN o[76]
    DIRECTION OUTPUT ;
    USE SIGNAL ;
    PORT
      LAYER M4 ;
        RECT  0 12.816 0.084 12.84 ;
    END
  END o[76]
  PIN o[77]
    DIRECTION OUTPUT ;
    USE SIGNAL ;
    PORT
      LAYER M4 ;
        RECT  0 12.912 0.084 12.936 ;
    END
  END o[77]
  PIN o[78]
    DIRECTION OUTPUT ;
    USE SIGNAL ;
    PORT
      LAYER M4 ;
        RECT  0 13.008 0.084 13.032 ;
    END
  END o[78]
  PIN o[79]
    DIRECTION OUTPUT ;
    USE SIGNAL ;
    PORT
      LAYER M4 ;
        RECT  0 13.104 0.084 13.128 ;
    END
  END o[79]
  PIN o[7]
    DIRECTION OUTPUT ;
    USE SIGNAL ;
    PORT
      LAYER M4 ;
        RECT  0 15.408 0.084 15.432 ;
    END
  END o[7]
  PIN o[80]
    DIRECTION OUTPUT ;
    USE SIGNAL ;
    PORT
      LAYER M4 ;
        RECT  0 13.2 0.084 13.224 ;
    END
  END o[80]
  PIN o[81]
    DIRECTION OUTPUT ;
    USE SIGNAL ;
    PORT
      LAYER M4 ;
        RECT  0 13.296 0.084 13.32 ;
    END
  END o[81]
  PIN o[82]
    DIRECTION OUTPUT ;
    USE SIGNAL ;
    PORT
      LAYER M4 ;
        RECT  0 13.392 0.084 13.416 ;
    END
  END o[82]
  PIN o[83]
    DIRECTION OUTPUT ;
    USE SIGNAL ;
    PORT
      LAYER M4 ;
        RECT  0 13.488 0.084 13.512 ;
    END
  END o[83]
  PIN o[84]
    DIRECTION OUTPUT ;
    USE SIGNAL ;
    PORT
      LAYER M4 ;
        RECT  0 13.584 0.084 13.608 ;
    END
  END o[84]
  PIN o[85]
    DIRECTION OUTPUT ;
    USE SIGNAL ;
    PORT
      LAYER M4 ;
        RECT  0 13.68 0.084 13.704 ;
    END
  END o[85]
  PIN o[86]
    DIRECTION OUTPUT ;
    USE SIGNAL ;
    PORT
      LAYER M4 ;
        RECT  0 13.776 0.084 13.8 ;
    END
  END o[86]
  PIN o[87]
    DIRECTION OUTPUT ;
    USE SIGNAL ;
    PORT
      LAYER M4 ;
        RECT  0 13.872 0.084 13.896 ;
    END
  END o[87]
  PIN o[88]
    DIRECTION OUTPUT ;
    USE SIGNAL ;
    PORT
      LAYER M4 ;
        RECT  0 13.968 0.084 13.992 ;
    END
  END o[88]
  PIN o[89]
    DIRECTION OUTPUT ;
    USE SIGNAL ;
    PORT
      LAYER M4 ;
        RECT  0 14.064 0.084 14.088 ;
    END
  END o[89]
  PIN o[8]
    DIRECTION OUTPUT ;
    USE SIGNAL ;
    PORT
      LAYER M4 ;
        RECT  0 15.504 0.084 15.528 ;
    END
  END o[8]
  PIN o[90]
    DIRECTION OUTPUT ;
    USE SIGNAL ;
    PORT
      LAYER M4 ;
        RECT  0 14.16 0.084 14.184 ;
    END
  END o[90]
  PIN o[91]
    DIRECTION OUTPUT ;
    USE SIGNAL ;
    PORT
      LAYER M4 ;
        RECT  0 14.256 0.084 14.28 ;
    END
  END o[91]
  PIN o[92]
    DIRECTION OUTPUT ;
    USE SIGNAL ;
    PORT
      LAYER M4 ;
        RECT  0 14.352 0.084 14.376 ;
    END
  END o[92]
  PIN o[93]
    DIRECTION OUTPUT ;
    USE SIGNAL ;
    PORT
      LAYER M4 ;
        RECT  0 14.448 0.084 14.472 ;
    END
  END o[93]
  PIN o[94]
    DIRECTION OUTPUT ;
    USE SIGNAL ;
    PORT
      LAYER M4 ;
        RECT  0 14.544 0.084 14.568 ;
    END
  END o[94]
  PIN o[95]
    DIRECTION OUTPUT ;
    USE SIGNAL ;
    PORT
      LAYER M4 ;
        RECT  0 14.64 0.084 14.664 ;
    END
  END o[95]
  PIN o[96]
    DIRECTION OUTPUT ;
    USE SIGNAL ;
    PORT
      LAYER M4 ;
        RECT  0 5.52 0.084 5.544 ;
    END
  END o[96]
  PIN o[97]
    DIRECTION OUTPUT ;
    USE SIGNAL ;
    PORT
      LAYER M4 ;
        RECT  0 5.616 0.084 5.64 ;
    END
  END o[97]
  PIN o[98]
    DIRECTION OUTPUT ;
    USE SIGNAL ;
    PORT
      LAYER M4 ;
        RECT  0 5.712 0.084 5.736 ;
    END
  END o[98]
  PIN o[99]
    DIRECTION OUTPUT ;
    USE SIGNAL ;
    PORT
      LAYER M4 ;
        RECT  0 5.808 0.084 5.832 ;
    END
  END o[99]
  PIN o[9]
    DIRECTION OUTPUT ;
    USE SIGNAL ;
    PORT
      LAYER M4 ;
        RECT  0 15.6 0.084 15.624 ;
    END
  END o[9]
  PIN rfi
    DIRECTION INPUT ;
    USE SIGNAL ;
    PORT
      LAYER M4 ;
        RECT  21.516 10.704 21.6 10.728 ;
    END
  END rfi
  PIN rfo
    DIRECTION OUTPUT ;
    USE SIGNAL ;
    PORT
      LAYER M4 ;
        RECT  0 11.472 0.084 11.496 ;
    END
  END rfo
  PIN rs
    DIRECTION INPUT ;
    USE SIGNAL ;
    PORT
      LAYER M5 ;
        RECT  10.992 0 11.016 0.084 ;
    END
  END rs
  PIN rso
    DIRECTION OUTPUT ;
    USE SIGNAL ;
    PORT
      LAYER M4 ;
        RECT  0 11.568 0.084 11.592 ;
    END
  END rso
  PIN VDD
    DIRECTION INOUT ;
    USE POWER ;
    PORT
      LAYER M5 ;
        RECT  18.792 2.151 18.912 19.449 ;
        RECT  16.092 2.151 16.212 19.449 ;
        RECT  13.392 2.151 13.512 19.449 ;
        RECT  10.692 2.151 10.812 19.449 ;
        RECT  7.992 2.151 8.112 19.449 ;
        RECT  5.292 2.151 5.412 19.449 ;
        RECT  2.592 2.151 2.712 19.449 ;
    END
  END VDD
  PIN VSS
    DIRECTION INOUT ;
    USE GROUND ;
    PORT
      LAYER M5 ;
        RECT  18.6 2.137 18.72 19.463 ;
        RECT  15.9 2.137 16.02 19.463 ;
        RECT  13.2 2.137 13.32 19.463 ;
        RECT  10.5 2.137 10.62 19.463 ;
        RECT  7.8 2.137 7.92 19.463 ;
        RECT  5.1 2.137 5.22 19.463 ;
        RECT  2.4 2.137 2.52 19.463 ;
    END
  END VSS
  OBS
    LAYER RVTN ;
     RECT  2.16 2.16 19.44 2.295 ;
     RECT  2.16 2.565 19.44 2.835 ;
     RECT  2.16 3.105 19.44 3.375 ;
     RECT  2.16 3.645 19.44 3.915 ;
     RECT  2.16 4.185 19.44 4.455 ;
     RECT  2.16 4.725 19.44 4.995 ;
     RECT  2.16 5.265 19.44 5.535 ;
     RECT  2.16 5.805 19.44 6.075 ;
     RECT  2.16 6.345 19.44 6.615 ;
     RECT  2.16 6.885 19.44 7.155 ;
     RECT  2.16 7.425 19.44 7.695 ;
     RECT  2.16 7.965 19.44 8.235 ;
     RECT  2.16 8.505 19.44 8.775 ;
     RECT  2.16 9.045 19.44 9.315 ;
     RECT  2.16 9.585 19.44 9.855 ;
     RECT  2.16 10.125 19.44 10.395 ;
     RECT  2.16 10.665 19.44 10.935 ;
     RECT  2.16 11.205 19.44 11.475 ;
     RECT  2.16 11.745 19.44 12.015 ;
     RECT  2.16 12.285 19.44 12.555 ;
     RECT  2.16 12.825 19.44 13.095 ;
     RECT  2.16 13.365 19.44 13.635 ;
     RECT  2.16 13.905 19.44 14.175 ;
     RECT  2.16 14.445 19.44 14.715 ;
     RECT  2.16 14.985 19.44 15.255 ;
     RECT  2.16 15.525 19.44 15.795 ;
     RECT  2.16 16.065 19.44 16.335 ;
     RECT  2.16 16.605 19.44 16.875 ;
     RECT  2.16 17.145 19.44 17.415 ;
     RECT  2.16 17.685 19.44 17.955 ;
     RECT  2.16 18.225 19.44 18.495 ;
     RECT  2.16 18.765 19.44 19.035 ;
     RECT  2.16 19.305 19.44 19.44 ;
    LAYER RVTP ;
     RECT  2.16 2.295 19.44 2.565 ;
     RECT  2.16 2.835 19.44 3.105 ;
     RECT  2.16 3.375 19.44 3.645 ;
     RECT  2.16 3.915 19.44 4.185 ;
     RECT  2.16 4.455 19.44 4.725 ;
     RECT  2.16 4.995 19.44 5.265 ;
     RECT  2.16 5.535 19.44 5.805 ;
     RECT  2.16 6.075 19.44 6.345 ;
     RECT  2.16 6.615 19.44 6.885 ;
     RECT  2.16 7.155 19.44 7.425 ;
     RECT  2.16 7.695 19.44 7.965 ;
     RECT  2.16 8.235 19.44 8.505 ;
     RECT  2.16 8.775 19.44 9.045 ;
     RECT  2.16 9.315 19.44 9.585 ;
     RECT  2.16 9.855 19.44 10.125 ;
     RECT  2.16 10.395 19.44 10.665 ;
     RECT  2.16 10.935 19.44 11.205 ;
     RECT  2.16 11.475 19.44 11.745 ;
     RECT  2.16 12.015 19.44 12.285 ;
     RECT  2.16 12.555 19.44 12.825 ;
     RECT  2.16 13.095 19.44 13.365 ;
     RECT  2.16 13.635 19.44 13.905 ;
     RECT  2.16 14.175 19.44 14.445 ;
     RECT  2.16 14.715 19.44 14.985 ;
     RECT  2.16 15.255 19.44 15.525 ;
     RECT  2.16 15.795 19.44 16.065 ;
     RECT  2.16 16.335 19.44 16.605 ;
     RECT  2.16 16.875 19.44 17.145 ;
     RECT  2.16 17.415 19.44 17.685 ;
     RECT  2.16 17.955 19.44 18.225 ;
     RECT  2.16 18.495 19.44 18.765 ;
     RECT  2.16 19.035 19.44 19.305 ;
    LAYER M1 ;
     RECT  2.16 2.151 19.44 19.449 ;
    LAYER M2 ;
     RECT  0.103 3.69 0.175 3.708 ;
     RECT  0.175 3.69 0.203 4.284 ;
     RECT  0.103 5.436 0.203 7.38 ;
     RECT  0.103 10.836 0.203 10.854 ;
     RECT  0.103 12.798 0.203 14.049 ;
     RECT  0.103 16.614 0.203 17.37 ;
     RECT  0.203 7.362 0.239 7.38 ;
     RECT  0.203 4.266 0.275 4.284 ;
     RECT  0.463 2.574 0.499 2.592 ;
     RECT  0.499 2.574 0.535 2.754 ;
     RECT  0.103 9.288 0.571 9.306 ;
     RECT  0.571 9.288 0.607 9.414 ;
     RECT  0.499 10.404 0.607 10.422 ;
     RECT  0.535 14.22 1.183 14.904 ;
     RECT  1.183 13.986 1.211 14.904 ;
     RECT  0.535 2.034 2.16 3.204 ;
     RECT  0.203 5.436 2.16 5.454 ;
     RECT  0.607 9.288 2.16 10.422 ;
     RECT  0.535 11.25 2.16 11.268 ;
     RECT  0.535 12.096 2.16 12.114 ;
     RECT  1.211 13.986 2.16 14.004 ;
     RECT  1.211 14.886 2.16 14.904 ;
     RECT  0.139 15.804 2.16 15.822 ;
     RECT  0.203 16.614 2.16 16.632 ;
     RECT  2.16 2.034 2.839 19.449 ;
     RECT  2.839 1.962 2.875 19.449 ;
     RECT  2.875 1.881 5.639 19.449 ;
     RECT  5.639 2.034 7.151 19.449 ;
     RECT  7.151 2.106 13.163 19.449 ;
     RECT  13.163 2.151 19.44 19.449 ;
     RECT  19.44 3.618 19.967 11.574 ;
     RECT  19.967 3.69 20.327 11.574 ;
     RECT  20.327 9.288 20.399 11.574 ;
     RECT  20.327 3.69 20.435 4.986 ;
     RECT  20.399 9.558 20.435 11.574 ;
     RECT  19.44 12.87 20.435 19.368 ;
     RECT  20.435 10.98 20.471 11.43 ;
     RECT  20.327 5.778 20.507 8.334 ;
     RECT  20.471 10.98 20.507 11.196 ;
     RECT  20.435 12.87 20.507 16.326 ;
     RECT  20.435 17.082 20.507 17.1 ;
     RECT  20.435 18.198 20.507 19.368 ;
     RECT  20.435 3.69 20.543 4.518 ;
     RECT  20.507 5.778 20.543 7.524 ;
     RECT  20.507 14.22 20.543 16.326 ;
     RECT  20.543 3.96 20.579 4.518 ;
     RECT  20.543 14.49 20.579 16.326 ;
     RECT  20.543 5.778 21.443 6.606 ;
     RECT  20.543 7.398 21.443 7.416 ;
     RECT  20.435 9.594 21.443 10.188 ;
     RECT  20.579 14.49 21.443 14.544 ;
     RECT  20.507 8.28 21.479 8.334 ;
     RECT  21.443 9.594 21.479 9.882 ;
     RECT  20.507 18.198 21.479 19.296 ;
     RECT  20.579 3.96 21.515 3.978 ;
     RECT  21.443 5.886 21.515 5.904 ;
     RECT  21.479 8.316 21.515 8.334 ;
     RECT  21.479 9.594 21.515 9.612 ;
     RECT  20.507 10.98 21.515 10.998 ;
     RECT  21.443 14.526 21.515 14.544 ;
     RECT  20.579 15.57 21.515 16.326 ;
     RECT  21.479 18.198 21.515 18.216 ;
     RECT  21.479 19.116 21.515 19.134 ;
    LAYER M3 ;
     RECT  2.88 1.876 2.898 1.957 ;
     RECT  5.616 1.876 5.634 1.957 ;
     RECT  2.844 1.957 2.898 2.029 ;
     RECT  5.58 1.957 5.634 2.029 ;
     RECT  2.844 2.029 3.402 2.101 ;
     RECT  2.844 2.101 3.438 2.143 ;
     RECT  5.508 2.029 5.634 2.143 ;
     RECT  7.128 2.029 7.146 2.143 ;
     RECT  11.016 1.531 11.034 2.143 ;
     RECT  13.14 2.101 13.158 2.143 ;
     RECT  2.415 2.143 3.438 2.191 ;
     RECT  5.115 2.143 5.634 2.191 ;
     RECT  7.128 2.143 7.905 2.219 ;
     RECT  2.415 2.191 3.87 2.227 ;
     RECT  2.34 2.227 3.87 2.299 ;
     RECT  0.54 2.029 0.558 2.347 ;
     RECT  2.34 2.299 4.194 2.371 ;
     RECT  5.115 2.191 6.21 2.371 ;
     RECT  7.815 2.219 7.905 2.413 ;
     RECT  13.14 2.143 13.305 2.413 ;
     RECT  15.915 2.143 16.005 2.413 ;
     RECT  18.615 2.143 18.705 2.413 ;
     RECT  2.34 2.371 6.21 2.569 ;
     RECT  10.515 2.143 11.034 2.641 ;
     RECT  15.915 2.413 16.197 2.641 ;
     RECT  0.108 2.347 0.558 2.669 ;
     RECT  2.34 2.569 6.93 2.669 ;
     RECT  13.14 2.413 13.497 2.731 ;
     RECT  10.515 2.641 11.07 2.803 ;
     RECT  7.815 2.413 8.097 2.911 ;
     RECT  13.104 2.731 13.497 2.911 ;
     RECT  18.615 2.413 18.897 2.911 ;
     RECT  7.815 2.911 8.154 3.001 ;
     RECT  15.915 2.641 16.614 3.037 ;
     RECT  18.36 2.911 18.897 3.037 ;
     RECT  7.815 3.001 8.19 3.073 ;
     RECT  18.36 3.037 18.954 3.073 ;
     RECT  12.564 2.911 13.497 3.109 ;
     RECT  18.288 3.073 18.954 3.145 ;
     RECT  15.915 3.037 16.65 3.181 ;
     RECT  17.676 3.145 18.954 3.181 ;
     RECT  7.776 3.073 8.19 3.271 ;
     RECT  12.564 3.109 13.698 3.379 ;
     RECT  10.515 2.803 11.214 3.415 ;
     RECT  15.372 3.181 18.954 3.451 ;
     RECT  12.384 3.379 13.77 3.541 ;
     RECT  14.508 3.181 14.526 3.541 ;
     RECT  10.152 3.415 11.214 3.577 ;
     RECT  12.384 3.541 14.526 3.613 ;
     RECT  15.3 3.451 18.954 3.613 ;
     RECT  0.144 2.669 0.558 3.676 ;
     RECT  10.08 3.577 11.214 3.685 ;
     RECT  19.944 3.613 19.962 3.685 ;
     RECT  2.34 2.669 6.678 3.721 ;
     RECT  12.384 3.613 18.954 3.721 ;
     RECT  19.944 3.685 20.538 3.721 ;
     RECT  2.304 3.721 6.678 3.811 ;
     RECT  7.776 3.271 8.226 3.811 ;
     RECT  0.108 3.676 0.558 3.821 ;
     RECT  2.304 3.811 8.226 3.839 ;
     RECT  9.54 3.685 11.214 3.839 ;
     RECT  9.828 3.839 11.214 3.919 ;
     RECT  12.384 3.721 20.538 3.919 ;
     RECT  2.34 3.839 8.226 3.955 ;
     RECT  21.492 3.955 21.51 4.013 ;
     RECT  2.34 3.955 8.586 4.109 ;
     RECT  9.828 3.919 20.538 4.492 ;
     RECT  9.828 4.492 20.574 4.649 ;
     RECT  2.415 4.109 8.586 4.801 ;
     RECT  0.144 3.821 0.558 4.877 ;
     RECT  2.415 4.801 8.802 5.131 ;
     RECT  2.304 5.131 8.802 5.161 ;
     RECT  2.304 5.161 9.162 5.189 ;
     RECT  0.144 4.877 0.198 5.419 ;
     RECT  19.836 4.649 20.574 5.515 ;
     RECT  2.34 5.189 9.162 5.639 ;
     RECT  10.515 4.649 18.99 5.701 ;
     RECT  10.224 5.701 18.99 5.707 ;
     RECT  19.8 5.515 20.574 5.707 ;
     RECT  21.42 5.419 21.438 5.803 ;
     RECT  10.224 5.707 20.574 5.809 ;
     RECT  9.036 5.639 9.162 5.845 ;
     RECT  9.9 5.809 20.574 5.845 ;
     RECT  21.42 5.803 21.51 5.909 ;
     RECT  9.036 5.845 20.574 6.221 ;
     RECT  2.34 5.639 8.097 6.691 ;
     RECT  2.304 6.691 8.097 7.195 ;
     RECT  9.036 6.221 20.538 7.195 ;
     RECT  0.108 5.419 0.198 7.243 ;
     RECT  2.304 7.195 20.538 7.349 ;
     RECT  0.108 7.243 0.342 7.385 ;
     RECT  21.42 5.909 21.438 7.421 ;
     RECT  7.38 7.349 20.538 7.661 ;
     RECT  7.38 7.661 20.502 7.691 ;
     RECT  0.216 7.385 0.342 7.723 ;
     RECT  7.38 7.691 9.054 7.763 ;
     RECT  2.304 7.349 6.39 7.889 ;
     RECT  0.216 7.723 0.594 8.107 ;
     RECT  7.38 7.763 8.514 8.159 ;
     RECT  7.38 8.159 8.097 8.167 ;
     RECT  9.9 7.691 20.502 8.231 ;
     RECT  2.34 7.889 6.39 8.239 ;
     RECT  7.272 8.167 8.097 8.239 ;
     RECT  21.492 8.203 21.51 8.275 ;
     RECT  21.456 8.275 21.51 8.333 ;
     RECT  0.108 8.107 0.594 8.395 ;
     RECT  2.34 8.239 8.097 8.779 ;
     RECT  2.304 8.779 8.097 8.807 ;
     RECT  9.9 8.231 20.322 8.971 ;
     RECT  2.304 8.807 6.75 9.005 ;
     RECT  21.492 8.333 21.51 9.259 ;
     RECT  0.108 8.395 0.63 9.311 ;
     RECT  21.456 9.259 21.51 9.355 ;
     RECT  0.576 9.311 0.63 9.419 ;
     RECT  21.42 9.355 21.51 9.617 ;
     RECT  9.9 8.971 20.43 9.661 ;
     RECT  2.34 9.005 6.75 9.751 ;
     RECT  7.815 8.807 8.097 9.751 ;
     RECT  9.828 9.661 20.43 9.887 ;
     RECT  0.612 9.419 0.63 9.923 ;
     RECT  10.008 9.887 20.43 9.931 ;
     RECT  21.42 9.617 21.474 10.193 ;
     RECT  2.34 9.751 8.097 10.201 ;
     RECT  0.504 10.399 0.522 10.651 ;
     RECT  10.008 9.931 20.502 10.699 ;
     RECT  10.008 10.699 20.538 10.705 ;
     RECT  0.144 10.651 0.522 10.828 ;
     RECT  9.54 10.705 20.538 10.829 ;
     RECT  9.54 10.829 20.502 10.867 ;
     RECT  8.928 10.867 20.502 10.931 ;
     RECT  0.108 10.828 0.522 10.939 ;
     RECT  21.492 10.507 21.51 11.003 ;
     RECT  20.376 10.931 20.502 11.039 ;
     RECT  0.108 10.939 1.17 11.117 ;
     RECT  20.412 11.039 20.502 11.201 ;
     RECT  0.144 11.117 1.17 11.227 ;
     RECT  8.928 10.931 19.494 11.273 ;
     RECT  0.144 11.227 1.242 11.405 ;
     RECT  2.304 10.201 8.097 11.419 ;
     RECT  8.928 11.273 19.458 11.419 ;
     RECT  20.412 11.201 20.466 11.435 ;
     RECT  2.304 11.419 19.458 11.507 ;
     RECT  2.304 11.507 19.314 11.543 ;
     RECT  20.412 11.435 20.43 11.579 ;
     RECT  10.08 11.543 19.314 11.705 ;
     RECT  9.036 11.543 9.342 11.975 ;
     RECT  0.144 11.405 1.17 11.981 ;
     RECT  2.304 11.543 8.154 12.283 ;
     RECT  9.324 11.975 9.342 12.559 ;
     RECT  10.08 11.705 18.897 12.559 ;
     RECT  9.324 12.559 18.897 12.631 ;
     RECT  2.304 12.283 8.586 12.721 ;
     RECT  9.324 12.631 19.026 12.721 ;
     RECT  0.144 11.981 0.594 12.793 ;
     RECT  2.304 12.721 19.026 13.019 ;
     RECT  2.415 13.019 19.026 13.027 ;
     RECT  20.484 12.865 20.502 13.099 ;
     RECT  2.415 13.027 19.062 13.171 ;
     RECT  20.412 13.099 20.502 13.195 ;
     RECT  0.108 12.793 0.594 13.229 ;
     RECT  19.908 13.195 20.502 13.433 ;
     RECT  20.196 13.433 20.502 13.675 ;
     RECT  1.152 13.915 1.17 13.963 ;
     RECT  2.415 13.171 19.134 13.981 ;
     RECT  20.196 13.675 20.538 14.059 ;
     RECT  0.108 13.229 0.198 14.06 ;
     RECT  2.415 13.981 19.314 14.141 ;
     RECT  9.684 14.141 19.314 14.155 ;
     RECT  20.196 14.059 20.574 14.155 ;
     RECT  1.152 13.963 1.278 14.189 ;
     RECT  0.144 14.06 0.198 14.215 ;
     RECT  1.152 14.189 1.206 14.215 ;
     RECT  0.144 14.215 1.206 14.243 ;
     RECT  21.492 14.251 21.51 14.443 ;
     RECT  21.42 14.443 21.51 14.513 ;
     RECT  21.492 14.513 21.51 14.549 ;
     RECT  2.415 14.141 8.838 14.639 ;
     RECT  0.144 14.243 0.558 14.923 ;
     RECT  3.528 14.639 8.838 14.989 ;
     RECT  9.684 14.155 20.574 14.989 ;
     RECT  3.528 14.989 20.574 15.017 ;
     RECT  3.528 15.017 20.538 15.053 ;
     RECT  0.108 14.923 0.558 15.115 ;
     RECT  0.108 15.115 1.17 15.293 ;
     RECT  2.415 14.639 2.754 15.421 ;
     RECT  3.528 15.053 9.306 15.421 ;
     RECT  2.415 15.421 9.306 15.592 ;
     RECT  10.224 15.053 20.538 15.719 ;
     RECT  2.304 15.592 9.306 15.799 ;
     RECT  0.108 15.293 0.558 15.917 ;
     RECT  2.304 15.799 9.522 15.989 ;
     RECT  2.304 15.989 9.45 16.061 ;
     RECT  2.415 16.061 9.45 16.169 ;
     RECT  9.432 16.169 9.45 16.259 ;
     RECT  21.492 15.565 21.51 16.331 ;
     RECT  2.415 16.169 8.658 16.529 ;
     RECT  10.296 15.719 20.538 16.645 ;
     RECT  10.224 16.645 20.538 16.891 ;
     RECT  1.152 16.795 1.17 16.973 ;
     RECT  9.684 16.891 20.538 16.973 ;
     RECT  9.684 16.973 20.502 17.105 ;
     RECT  0.108 15.917 0.162 17.179 ;
     RECT  9.684 17.105 20.43 17.339 ;
     RECT  0.108 17.179 0.234 17.375 ;
     RECT  0.144 17.375 0.234 17.501 ;
     RECT  0.216 17.501 0.234 17.549 ;
     RECT  2.415 16.529 8.154 17.609 ;
     RECT  2.415 17.609 6.93 17.611 ;
     RECT  7.815 17.609 8.154 17.689 ;
     RECT  2.376 17.611 6.93 17.761 ;
     RECT  7.815 17.689 8.226 17.851 ;
     RECT  9.684 17.339 19.062 17.923 ;
     RECT  9.648 17.923 19.062 17.995 ;
     RECT  7.815 17.851 8.406 18.059 ;
     RECT  9.36 17.995 19.062 18.059 ;
     RECT  21.492 17.803 21.51 18.091 ;
     RECT  7.815 18.059 8.226 18.185 ;
     RECT  9.36 18.059 10.926 18.193 ;
     RECT  2.304 17.761 6.93 18.221 ;
     RECT  21.456 18.091 21.51 18.221 ;
     RECT  11.772 18.059 19.062 18.227 ;
     RECT  19.836 17.339 20.43 18.283 ;
     RECT  9.252 18.193 10.926 18.461 ;
     RECT  11.952 18.227 19.062 18.499 ;
     RECT  19.836 18.283 20.502 18.499 ;
     RECT  21.456 18.221 21.474 18.523 ;
     RECT  21.42 18.523 21.474 18.701 ;
     RECT  9.972 18.461 10.926 18.725 ;
     RECT  10.008 18.725 10.926 18.761 ;
     RECT  11.952 18.499 20.502 18.761 ;
     RECT  21.456 18.701 21.474 18.955 ;
     RECT  2.304 18.221 6.426 19.031 ;
     RECT  3.456 19.031 6.426 19.067 ;
     RECT  11.952 18.761 19.422 19.075 ;
     RECT  5.004 19.067 6.426 19.139 ;
     RECT  21.456 18.955 21.51 19.139 ;
     RECT  2.304 19.031 2.697 19.187 ;
     RECT  7.815 18.185 8.097 19.187 ;
     RECT  2.304 19.187 2.574 19.229 ;
     RECT  3.456 19.067 4.194 19.229 ;
     RECT  5.115 19.139 6.426 19.229 ;
     RECT  10.515 18.761 10.926 19.229 ;
     RECT  11.844 19.075 19.422 19.229 ;
     RECT  4.176 19.229 4.194 19.265 ;
     RECT  6.408 19.229 6.426 19.265 ;
     RECT  12.132 19.229 14.85 19.265 ;
     RECT  12.672 19.265 14.85 19.301 ;
     RECT  15.768 19.229 19.422 19.301 ;
     RECT  21.456 19.139 21.474 19.301 ;
     RECT  5.115 19.229 5.598 19.337 ;
     RECT  13.215 19.301 14.85 19.337 ;
     RECT  15.915 19.301 17.01 19.337 ;
     RECT  17.964 19.301 19.422 19.337 ;
     RECT  13.215 19.337 14.526 19.373 ;
     RECT  15.915 19.337 16.578 19.373 ;
     RECT  18.036 19.337 18.705 19.373 ;
     RECT  20.484 18.761 20.502 19.373 ;
     RECT  2.415 19.229 2.505 19.457 ;
     RECT  5.115 19.337 5.205 19.457 ;
     RECT  7.815 19.187 7.905 19.457 ;
     RECT  10.515 19.229 10.605 19.457 ;
     RECT  13.215 19.373 13.305 19.457 ;
     RECT  15.915 19.373 16.005 19.457 ;
     RECT  18.615 19.373 18.705 19.457 ;
    LAYER M4 ;
     RECT  0.06 2.448 0.097 8.52 ;
     RECT  0.06 10.704 0.133 17.736 ;
     RECT  0.097 2.352 2.408 8.52 ;
     RECT  0.133 10.656 2.408 17.736 ;
     RECT  2.408 2.148 2.512 19.452 ;
     RECT  2.512 2.352 2.704 19.182 ;
     RECT  2.704 2.352 3.413 18.216 ;
     RECT  3.413 2.496 5.108 18.216 ;
     RECT  5.108 2.148 5.212 19.452 ;
     RECT  5.212 2.418 5.404 19.182 ;
     RECT  5.404 2.592 5.753 18.216 ;
     RECT  5.753 3.6 5.933 18.216 ;
     RECT  5.933 3.6 6.257 17.976 ;
     RECT  5.753 2.592 7.808 2.616 ;
     RECT  6.257 3.84 7.808 17.976 ;
     RECT  7.808 2.148 7.912 19.452 ;
     RECT  7.912 2.418 8.104 19.182 ;
     RECT  8.104 4.416 8.309 4.488 ;
     RECT  8.104 6.144 9.107 17.976 ;
     RECT  9.107 11.664 9.241 17.976 ;
     RECT  8.309 4.416 10.508 4.44 ;
     RECT  9.107 6.144 10.508 10.68 ;
     RECT  9.241 11.664 10.508 18.456 ;
     RECT  10.508 2.148 10.612 19.452 ;
     RECT  10.612 2.148 10.804 19.182 ;
     RECT  10.933 1.824 10.961 1.848 ;
     RECT  10.961 1.536 11.045 1.848 ;
     RECT  10.885 0.096 11.123 0.12 ;
     RECT  11.045 1.824 11.123 1.848 ;
     RECT  10.804 4.416 12.049 18.456 ;
     RECT  12.049 4.416 12.733 18.744 ;
     RECT  12.133 3.408 12.985 3.432 ;
     RECT  12.733 4.416 12.985 19.08 ;
     RECT  12.985 3.408 13.057 19.08 ;
     RECT  13.057 3.408 13.208 19.128 ;
     RECT  13.208 2.148 13.312 19.452 ;
     RECT  13.312 2.418 13.504 19.368 ;
     RECT  13.504 4.128 14.533 11.112 ;
     RECT  13.504 12.528 14.533 19.368 ;
     RECT  14.533 4.128 14.537 19.368 ;
     RECT  14.537 4.128 15.757 19.224 ;
     RECT  15.757 4.128 15.829 19.272 ;
     RECT  15.829 3.84 15.865 19.272 ;
     RECT  15.865 3.696 15.908 19.272 ;
     RECT  15.908 2.148 16.012 19.452 ;
     RECT  16.012 2.418 16.204 19.272 ;
     RECT  16.204 3.696 16.373 19.272 ;
     RECT  16.373 4.128 16.481 19.272 ;
     RECT  16.481 4.128 16.661 19.224 ;
     RECT  16.661 10.08 17.021 19.224 ;
     RECT  16.661 4.128 17.485 9.096 ;
     RECT  17.485 4.08 18.608 9.096 ;
     RECT  17.021 10.176 18.608 19.224 ;
     RECT  18.608 2.148 18.712 19.452 ;
     RECT  18.712 2.418 18.904 19.182 ;
     RECT  18.904 3.888 19.897 10.344 ;
     RECT  18.904 13.488 19.897 18.792 ;
     RECT  19.897 3.792 20.329 10.632 ;
     RECT  19.897 13.2 20.401 18.792 ;
     RECT  20.329 3.792 20.437 10.728 ;
     RECT  20.401 13.104 20.473 18.792 ;
     RECT  20.437 3.792 20.549 10.824 ;
     RECT  20.473 13.008 21.445 18.888 ;
     RECT  20.549 3.792 21.564 10.728 ;
     RECT  21.445 13.008 21.564 19.08 ;
    LAYER M5 ;
     RECT  10.896 0.016 11.016 0.085 ;
     RECT  10.896 0.085 11.112 0.131 ;
     RECT  10.992 0.131 11.112 1.813 ;
     RECT  10.944 1.813 11.112 1.859 ;
     RECT  10.944 1.859 10.968 2.137 ;
     RECT  2.4 2.137 2.52 2.151 ;
     RECT  5.1 2.137 5.22 2.151 ;
     RECT  7.8 2.137 7.92 2.151 ;
     RECT  13.2 2.137 13.32 2.151 ;
     RECT  15.9 2.137 16.02 2.151 ;
     RECT  18.6 2.137 18.72 2.151 ;
     RECT  0.144 2.581 0.168 2.867 ;
     RECT  12.144 3.397 12.168 3.925 ;
     RECT  13.2 2.151 13.512 3.925 ;
     RECT  0.144 4.117 0.168 4.499 ;
     RECT  12.144 3.925 13.512 4.691 ;
     RECT  2.4 2.151 2.712 5.269 ;
     RECT  2.4 5.269 2.904 5.603 ;
     RECT  5.1 2.151 5.412 5.893 ;
     RECT  4.464 5.893 5.412 6.035 ;
     RECT  13.104 4.691 13.512 6.517 ;
     RECT  12.912 6.517 13.512 6.659 ;
     RECT  13.104 6.659 13.512 6.805 ;
     RECT  2.4 5.603 2.712 7.141 ;
     RECT  13.104 6.805 13.944 7.187 ;
     RECT  2.4 7.141 2.904 7.283 ;
     RECT  0.144 7.669 0.168 7.955 ;
     RECT  2.4 7.283 2.808 8.003 ;
     RECT  11.952 6.709 11.976 8.051 ;
     RECT  13.2 7.187 13.944 8.485 ;
     RECT  15.9 2.151 16.212 8.485 ;
     RECT  13.056 8.485 13.944 8.531 ;
     RECT  13.056 8.531 13.512 9.637 ;
     RECT  15.312 8.485 16.212 9.827 ;
     RECT  15.36 9.827 16.212 10.019 ;
     RECT  7.8 2.151 8.112 10.165 ;
     RECT  15.456 10.019 16.212 11.413 ;
     RECT  7.8 10.165 9.096 11.459 ;
     RECT  10.5 2.137 10.968 11.459 ;
     RECT  13.008 9.637 13.512 11.459 ;
     RECT  15.168 11.413 16.212 12.035 ;
     RECT  15.456 12.035 16.212 12.659 ;
     RECT  13.056 11.459 13.512 12.949 ;
     RECT  15.504 12.659 16.212 12.997 ;
     RECT  13.056 12.949 13.608 13.669 ;
     RECT  15.504 12.997 16.536 14.099 ;
     RECT  15.504 14.099 16.344 14.291 ;
     RECT  12.528 13.669 13.608 14.773 ;
     RECT  10.5 11.459 10.812 15.541 ;
     RECT  12 14.773 13.656 15.541 ;
     RECT  10.5 15.541 13.656 15.973 ;
     RECT  15.9 14.291 16.344 16.595 ;
     RECT  10.5 15.973 13.992 16.643 ;
     RECT  10.5 16.643 11.784 16.883 ;
     RECT  13.2 16.643 13.992 17.075 ;
     RECT  14.832 17.557 14.856 18.179 ;
     RECT  2.4 8.003 2.712 19.449 ;
     RECT  5.1 6.035 5.412 19.449 ;
     RECT  7.8 11.459 8.112 19.449 ;
     RECT  10.5 16.883 10.812 19.449 ;
     RECT  13.2 17.075 13.512 19.449 ;
     RECT  15.9 16.595 16.212 19.449 ;
     RECT  18.6 2.151 18.912 19.449 ;
     RECT  2.4 19.449 2.52 19.463 ;
     RECT  5.1 19.449 5.22 19.463 ;
     RECT  7.8 19.449 7.92 19.463 ;
     RECT  10.5 19.449 10.62 19.463 ;
     RECT  13.2 19.449 13.32 19.463 ;
     RECT  15.9 19.449 16.02 19.463 ;
     RECT  18.6 19.449 18.72 19.463 ;
  END
END hbfd_rly_136_EW_rrfc
END LIBRARY
